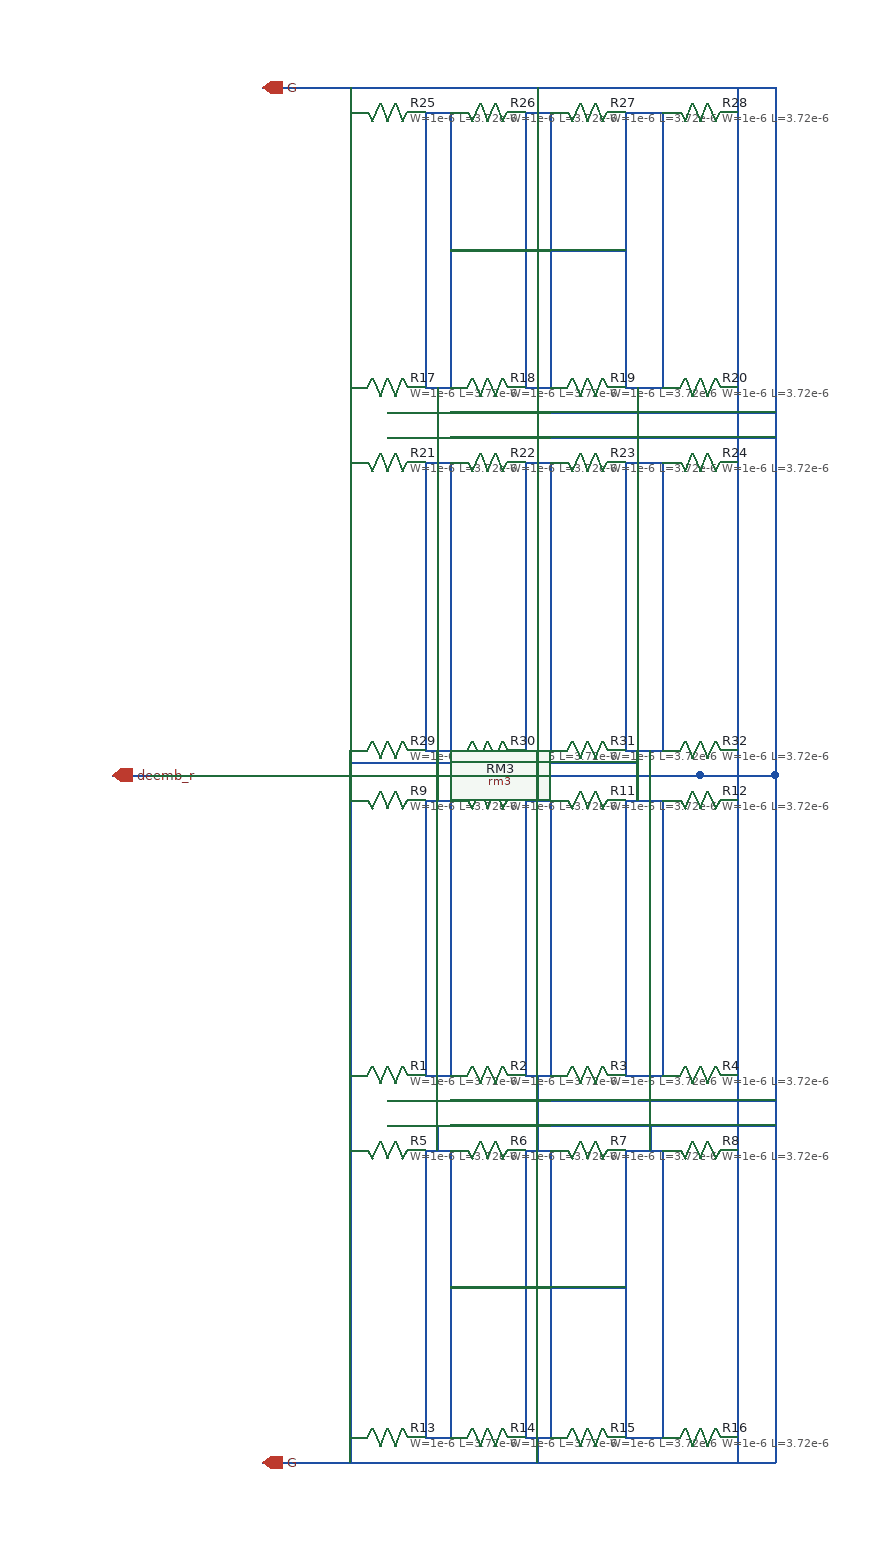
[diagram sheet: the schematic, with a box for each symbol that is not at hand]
v {xschem version=3.4.8RC file_version=1.3}
G {}
K {}
V {}
S {}
F {}
E {}
N 220 -310 470 -310 {lab=G}
N 220 -290 470 -290 {lab=G}
N 220 -20 470 -20 {lab=G}
N 220 -570 470 -570 {lab=G}
N 470 -310 530 -310 {lab=G}
N 470 -290 530 -290 {lab=G}
N 530 -570 530 -20 {lab=G}
N 470 -20 530 -20 {lab=G}
N 120 -20 220 -20 {lab=G}
N 220 -860 470 -860 {lab=G}
N 220 -840 470 -840 {lab=G}
N 220 -570 470 -570 {lab=G}
N 220 -1120 470 -1120 {lab=G}
N 470 -860 530 -860 {lab=G}
N 470 -840 530 -840 {lab=G}
N 470 -1120 530 -1120 {lab=G}
N 530 -1120 530 -570 {lab=G}
N 120 -1120 220 -1120 {lab=G}
N 120 -570 190 -570 {lab=deemb_r}
N 190 -1100 190 -880 {lab=G}
N 250 -1100 250 -880 {lab=G}
N 270 -1100 270 -880 {lab=G}
N 330 -1100 330 -880 {lab=G}
N 350 -1100 350 -880 {lab=G}
N 410 -1100 410 -880 {lab=G}
N 440 -1100 440 -880 {lab=G}
N 500 -1100 500 -880 {lab=G}
N 190 -820 190 -600 {lab=G}
N 250 -820 250 -600 {lab=deemb_r}
N 270 -820 270 -600 {lab=deemb_r}
N 330 -820 330 -600 {lab=G}
N 350 -820 350 -600 {lab=G}
N 410 -820 410 -600 {lab=deemb_r}
N 440 -820 440 -600 {lab=deemb_r}
N 500 -820 500 -600 {lab=G}
N 500 -600 500 -590 {lab=G}
N 440 -600 440 -590 {lab=deemb_r}
N 410 -600 410 -590 {lab=deemb_r}
N 350 -600 350 -590 {lab=G}
N 330 -600 330 -590 {lab=G}
N 270 -600 270 -590 {lab=deemb_r}
N 250 -600 250 -590 {lab=deemb_r}
N 190 -600 190 -590 {lab=G}
N 190 -550 190 -330 {lab=G}
N 250 -550 250 -330 {lab=deemb_r}
N 270 -550 270 -330 {lab=deemb_r}
N 330 -550 330 -330 {lab=G}
N 350 -550 350 -330 {lab=G}
N 410 -550 410 -330 {lab=deemb_r}
N 440 -550 440 -330 {lab=deemb_r}
N 500 -550 500 -330 {lab=G}
N 190 -270 190 -50 {lab=G}
N 250 -270 250 -50 {lab=G}
N 270 -270 270 -50 {lab=G}
N 330 -270 330 -50 {lab=G}
N 350 -270 350 -50 {lab=G}
N 410 -270 410 -50 {lab=G}
N 440 -270 440 -50 {lab=G}
N 500 -270 500 -50 {lab=G}
N 190 -50 190 -40 {lab=G}
N 250 -50 250 -40 {lab=G}
N 270 -50 270 -40 {lab=G}
N 330 -50 330 -40 {lab=G}
N 350 -50 350 -40 {lab=G}
N 410 -50 410 -40 {lab=G}
N 440 -50 440 -40 {lab=G}
N 500 -50 500 -40 {lab=G}
N 470 -570 530 -570 {lab=G}
N 190 -1120 190 -1100 {lab=G}
N 190 -880 190 -820 {lab=G}
N 190 -330 190 -270 {lab=G}
N 190 -40 190 -20 {lab=G}
N 330 -40 350 -40 {lab=G}
N 340 -40 340 -20 {lab=G}
N 330 -270 350 -270 {lab=G}
N 330 -330 350 -330 {lab=G}
N 340 -330 340 -270 {lab=G}
N 330 -550 350 -550 {lab=G}
N 330 -590 350 -590 {lab=G}
N 340 -590 340 -550 {lab=G}
N 330 -820 350 -820 {lab=G}
N 330 -880 350 -880 {lab=G}
N 340 -880 340 -820 {lab=G}
N 330 -1100 350 -1100 {lab=G}
N 340 -1120 340 -1100 {lab=G}
N 500 -1110 500 -1100 {lab=G}
N 500 -1120 500 -1110 {lab=G}
N 500 -880 500 -820 {lab=G}
N 500 -590 500 -550 {lab=G}
N 500 -330 500 -270 {lab=G}
N 500 -40 500 -20 {lab=G}
N 250 -270 270 -270 {lab=G}
N 410 -270 440 -270 {lab=G}
N 250 -40 270 -40 {lab=G}
N 410 -40 440 -40 {lab=G}
N 270 -160 410 -160 {lab=G}
N 250 -1100 270 -1100 {lab=G}
N 410 -1100 440 -1100 {lab=G}
N 410 -880 440 -880 {lab=G}
N 250 -880 270 -880 {lab=G}
N 250 -820 270 -820 {lab=deemb_r}
N 410 -820 440 -820 {lab=deemb_r}
N 410 -590 440 -590 {lab=deemb_r}
N 250 -590 270 -590 {lab=deemb_r}
N 250 -550 270 -550 {lab=deemb_r}
N 410 -550 440 -550 {lab=deemb_r}
N 410 -330 440 -330 {lab=deemb_r}
N 250 -330 270 -330 {lab=deemb_r}
N 270 -990 410 -990 {lab=G}
N 260 -590 260 -550 {lab=deemb_r}
N 420 -590 420 -550 {lab=deemb_r}
N 190 -580 260 -580 {lab=deemb_r}
N 190 -580 190 -570 {lab=deemb_r}
N 260 -290 260 -270 {lab=G}
N 430 -290 430 -270 {lab=G}
N 260 -880 260 -860 {lab=G}
N 420 -880 420 -860 {lab=G}
N 260 -580 420 -580 {lab=deemb_r}
C {symbols/ppolyf_u_1k_6p0.sym} 220 -330 3 0 {name=R1
W=1e-6
L=3.72e-6
model=ppolyf_u_1k_6p0
spiceprefix=X
m=5}
C {symbols/ppolyf_u_1k_6p0.sym} 300 -330 3 0 {name=R2
W=1e-6
L=3.72e-6
model=ppolyf_u_1k_6p0
spiceprefix=X
m=5}
C {symbols/ppolyf_u_1k_6p0.sym} 380 -330 3 0 {name=R3
W=1e-6
L=3.72e-6
model=ppolyf_u_1k_6p0
spiceprefix=X
m=5}
C {symbols/ppolyf_u_1k_6p0.sym} 470 -330 3 0 {name=R4
W=1e-6
L=3.72e-6
model=ppolyf_u_1k_6p0
spiceprefix=X
m=5}
C {symbols/ppolyf_u_1k_6p0.sym} 220 -270 3 1 {name=R5
W=1e-6
L=3.72e-6
model=ppolyf_u_1k_6p0
spiceprefix=X
m=5}
C {symbols/ppolyf_u_1k_6p0.sym} 300 -270 3 1 {name=R6
W=1e-6
L=3.72e-6
model=ppolyf_u_1k_6p0
spiceprefix=X
m=5}
C {symbols/ppolyf_u_1k_6p0.sym} 380 -270 3 1 {name=R7
W=1e-6
L=3.72e-6
model=ppolyf_u_1k_6p0
spiceprefix=X
m=5}
C {symbols/ppolyf_u_1k_6p0.sym} 470 -270 3 1 {name=R8
W=1e-6
L=3.72e-6
model=ppolyf_u_1k_6p0
spiceprefix=X
m=5}
C {symbols/ppolyf_u_1k_6p0.sym} 220 -550 3 1 {name=R9
W=1e-6
L=3.72e-6
model=ppolyf_u_1k_6p0
spiceprefix=X
m=5}
C {symbols/ppolyf_u_1k_6p0.sym} 300 -550 3 1 {name=R10
W=1e-6
L=3.72e-6
model=ppolyf_u_1k_6p0
spiceprefix=X
m=5}
C {symbols/ppolyf_u_1k_6p0.sym} 380 -550 3 1 {name=R11
W=1e-6
L=3.72e-6
model=ppolyf_u_1k_6p0
spiceprefix=X
m=5}
C {symbols/ppolyf_u_1k_6p0.sym} 470 -550 3 1 {name=R12
W=1e-6
L=3.72e-6
model=ppolyf_u_1k_6p0
spiceprefix=X
m=5}
C {symbols/ppolyf_u_1k_6p0.sym} 220 -40 3 0 {name=R13
W=1e-6
L=3.72e-6
model=ppolyf_u_1k_6p0
spiceprefix=X
m=5}
C {symbols/ppolyf_u_1k_6p0.sym} 300 -40 3 0 {name=R14
W=1e-6
L=3.72e-6
model=ppolyf_u_1k_6p0
spiceprefix=X
m=5}
C {symbols/ppolyf_u_1k_6p0.sym} 380 -40 3 0 {name=R15
W=1e-6
L=3.72e-6
model=ppolyf_u_1k_6p0
spiceprefix=X
m=5}
C {symbols/ppolyf_u_1k_6p0.sym} 470 -40 3 0 {name=R16
W=1e-6
L=3.72e-6
model=ppolyf_u_1k_6p0
spiceprefix=X
m=5}
C {symbols/ppolyf_u_1k_6p0.sym} 220 -880 3 0 {name=R17
W=1e-6
L=3.72e-6
model=ppolyf_u_1k_6p0
spiceprefix=X
m=5}
C {symbols/ppolyf_u_1k_6p0.sym} 300 -880 3 0 {name=R18
W=1e-6
L=3.72e-6
model=ppolyf_u_1k_6p0
spiceprefix=X
m=5}
C {symbols/ppolyf_u_1k_6p0.sym} 380 -880 3 0 {name=R19
W=1e-6
L=3.72e-6
model=ppolyf_u_1k_6p0
spiceprefix=X
m=5}
C {symbols/ppolyf_u_1k_6p0.sym} 470 -880 3 0 {name=R20
W=1e-6
L=3.72e-6
model=ppolyf_u_1k_6p0
spiceprefix=X
m=5}
C {symbols/ppolyf_u_1k_6p0.sym} 220 -820 3 1 {name=R21
W=1e-6
L=3.72e-6
model=ppolyf_u_1k_6p0
spiceprefix=X
m=5}
C {symbols/ppolyf_u_1k_6p0.sym} 300 -820 3 1 {name=R22
W=1e-6
L=3.72e-6
model=ppolyf_u_1k_6p0
spiceprefix=X
m=5}
C {symbols/ppolyf_u_1k_6p0.sym} 380 -820 3 1 {name=R23
W=1e-6
L=3.72e-6
model=ppolyf_u_1k_6p0
spiceprefix=X
m=5}
C {symbols/ppolyf_u_1k_6p0.sym} 470 -820 3 1 {name=R24
W=1e-6
L=3.72e-6
model=ppolyf_u_1k_6p0
spiceprefix=X
m=5}
C {symbols/ppolyf_u_1k_6p0.sym} 220 -1100 3 1 {name=R25
W=1e-6
L=3.72e-6
model=ppolyf_u_1k_6p0
spiceprefix=X
m=5}
C {symbols/ppolyf_u_1k_6p0.sym} 300 -1100 3 1 {name=R26
W=1e-6
L=3.72e-6
model=ppolyf_u_1k_6p0
spiceprefix=X
m=5}
C {symbols/ppolyf_u_1k_6p0.sym} 380 -1100 3 1 {name=R27
W=1e-6
L=3.72e-6
model=ppolyf_u_1k_6p0
spiceprefix=X
m=5}
C {symbols/ppolyf_u_1k_6p0.sym} 470 -1100 3 1 {name=R28
W=1e-6
L=3.72e-6
model=ppolyf_u_1k_6p0
spiceprefix=X
m=5}
C {symbols/ppolyf_u_1k_6p0.sym} 220 -590 3 0 {name=R29
W=1e-6
L=3.72e-6
model=ppolyf_u_1k_6p0
spiceprefix=X
m=5}
C {symbols/ppolyf_u_1k_6p0.sym} 300 -590 3 0 {name=R30
W=1e-6
L=3.72e-6
model=ppolyf_u_1k_6p0
spiceprefix=X
m=5}
C {symbols/ppolyf_u_1k_6p0.sym} 380 -590 3 0 {name=R31
W=1e-6
L=3.72e-6
model=ppolyf_u_1k_6p0
spiceprefix=X
m=5}
C {symbols/ppolyf_u_1k_6p0.sym} 470 -590 3 0 {name=R32
W=1e-6
L=3.72e-6
model=ppolyf_u_1k_6p0
spiceprefix=X
m=5}
C {iopin.sym} 120 -1120 0 1 {name=p1 lab=G}
C {iopin.sym} 0 -570 0 1 {name=p2 lab=deemb_r}
C {iopin.sym} 120 -20 0 1 {name=p3 lab=G}
N 0 -570 30 -570 {lab=deemb_r}
N 90 -570 120 -570 {lab=deemb_r_m1}
C {symbols/rm3.sym} 60 -570 1 0 {name=RM3
W=1.62e-6
L=1e-6
model=rm3
spiceprefix=X
m=1}
